VERSION 5.8 ;
BUSBITCHARS "[]" ;
DIVIDERCHAR "/" ;
UNITS
    DATABASE MICRONS 1000 ;
END UNITS

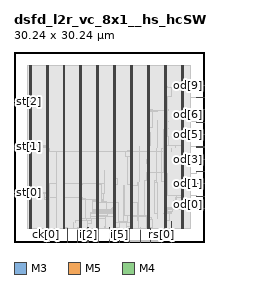
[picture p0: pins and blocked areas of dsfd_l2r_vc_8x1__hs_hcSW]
MACRO dsfd_l2r_vc_8x1__hs_hcSW
  FOREIGN dsfd_l2r_vc_8x1__hs_hcSW 0 0 ;
  CLASS BLOCK ;
  SIZE 30.24 BY 30.24 ;
  PIN ck[0]
    DIRECTION INPUT ;
    USE SIGNAL ;
    PORT
      LAYER M3 ;
        RECT  5.148 0 5.166 0.144 ;
    END
    PORT
      LAYER M3 ;
        RECT  5.148 0.108 5.166 0.173 ;
    END
  END ck[0]
  PIN cks[0]
    DIRECTION INPUT ;
    USE SIGNAL ;
    PORT
      LAYER M5 ;
        RECT  6.816 0 6.84 0.192 ;
    END
    PORT
      LAYER M5 ;
        RECT  6.816 0.144 6.84 2.137 ;
    END
  END cks[0]
  PIN fo[0]
    DIRECTION OUTPUT ;
    USE SIGNAL ;
    PORT
      LAYER M4 ;
        RECT  30.048 5.328 30.24 5.352 ;
    END
    PORT
      LAYER M4 ;
        RECT  27.004 5.328 30.06 5.352 ;
    END
  END fo[0]
  PIN i[0]
    DIRECTION INPUT ;
    USE SIGNAL ;
    PORT
      LAYER M3 ;
        RECT  8.46 0 8.478 0.144 ;
    END
    PORT
      LAYER M3 ;
        RECT  8.46 0.108 8.478 2.143 ;
    END
  END i[0]
  PIN i[1]
    DIRECTION INPUT ;
    USE SIGNAL ;
    PORT
      LAYER M5 ;
        RECT  10.128 0 10.152 0.192 ;
    END
    PORT
      LAYER M5 ;
        RECT  10.128 0.144 10.152 1.763 ;
    END
  END i[1]
  PIN i[2]
    DIRECTION INPUT ;
    USE SIGNAL ;
    PORT
      LAYER M3 ;
        RECT  11.772 0 11.79 0.144 ;
    END
    PORT
      LAYER M3 ;
        RECT  11.772 0.108 11.79 2.255 ;
    END
  END i[2]
  PIN i[3]
    DIRECTION INPUT ;
    USE SIGNAL ;
    PORT
      LAYER M5 ;
        RECT  13.44 0 13.464 0.192 ;
    END
    PORT
      LAYER M5 ;
        RECT  13.44 0.144 13.464 2.137 ;
    END
  END i[3]
  PIN i[4]
    DIRECTION INPUT ;
    USE SIGNAL ;
    PORT
      LAYER M3 ;
        RECT  15.12 0 15.138 0.144 ;
    END
    PORT
      LAYER M3 ;
        RECT  15.12 0.108 15.138 2.255 ;
    END
  END i[4]
  PIN i[5]
    DIRECTION INPUT ;
    USE SIGNAL ;
    PORT
      LAYER M5 ;
        RECT  16.752 0 16.776 0.192 ;
    END
    PORT
      LAYER M5 ;
        RECT  16.752 0.144 16.776 1.763 ;
    END
  END i[5]
  PIN i[6]
    DIRECTION INPUT ;
    USE SIGNAL ;
    PORT
      LAYER M3 ;
        RECT  18.432 0 18.45 0.144 ;
    END
    PORT
      LAYER M3 ;
        RECT  18.432 0.108 18.45 0.139 ;
    END
    PORT
      LAYER M3 ;
        RECT  17.856 0.139 18.45 2.143 ;
    END
  END i[6]
  PIN i[7]
    DIRECTION INPUT ;
    USE SIGNAL ;
    PORT
      LAYER M5 ;
        RECT  20.112 0 20.136 0.192 ;
    END
    PORT
      LAYER M5 ;
        RECT  20.112 0.144 20.136 1.763 ;
    END
  END i[7]
  PIN i[8]
    DIRECTION INPUT ;
    USE SIGNAL ;
    PORT
      LAYER M3 ;
        RECT  21.744 0 21.762 0.144 ;
    END
    PORT
      LAYER M3 ;
        RECT  21.744 0.108 21.762 2.143 ;
    END
  END i[8]
  PIN od[0]
    DIRECTION OUTPUT ;
    USE SIGNAL ;
    PORT
      LAYER M4 ;
        RECT  30.048 7.296 30.24 7.32 ;
    END
    PORT
      LAYER M4 ;
        RECT  29.041 7.296 30.06 7.32 ;
    END
  END od[0]
  PIN od[1]
    DIRECTION OUTPUT ;
    USE SIGNAL ;
    PORT
      LAYER M4 ;
        RECT  30.048 9.264 30.24 9.288 ;
    END
    PORT
      LAYER M4 ;
        RECT  29.077 9.264 30.06 9.288 ;
    END
  END od[1]
  PIN od[2]
    DIRECTION OUTPUT ;
    USE SIGNAL ;
    PORT
      LAYER M4 ;
        RECT  30.048 11.184 30.24 11.208 ;
    END
    PORT
      LAYER M4 ;
        RECT  29.077 11.184 30.06 11.208 ;
    END
  END od[2]
  PIN od[3]
    DIRECTION OUTPUT ;
    USE SIGNAL ;
    PORT
      LAYER M4 ;
        RECT  30.048 13.152 30.24 13.176 ;
    END
    PORT
      LAYER M4 ;
        RECT  29.653 13.152 30.06 13.176 ;
    END
  END od[3]
  PIN od[4]
    DIRECTION OUTPUT ;
    USE SIGNAL ;
    PORT
      LAYER M4 ;
        RECT  30.048 15.12 30.24 15.144 ;
    END
    PORT
      LAYER M4 ;
        RECT  29.041 15.12 30.06 15.144 ;
    END
  END od[4]
  PIN od[5]
    DIRECTION OUTPUT ;
    USE SIGNAL ;
    PORT
      LAYER M4 ;
        RECT  30.048 17.088 30.24 17.112 ;
    END
    PORT
      LAYER M4 ;
        RECT  29.077 17.088 30.06 17.112 ;
    END
  END od[5]
  PIN od[6]
    DIRECTION OUTPUT ;
    USE SIGNAL ;
    PORT
      LAYER M4 ;
        RECT  30.048 19.056 30.24 19.08 ;
    END
    PORT
      LAYER M4 ;
        RECT  29.077 19.056 30.06 19.08 ;
    END
  END od[6]
  PIN od[7]
    DIRECTION OUTPUT ;
    USE SIGNAL ;
    PORT
      LAYER M4 ;
        RECT  30.048 21.024 30.24 21.048 ;
    END
    PORT
      LAYER M4 ;
        RECT  29.077 21.024 30.06 21.048 ;
    END
  END od[7]
  PIN od[8]
    DIRECTION OUTPUT ;
    USE SIGNAL ;
    PORT
      LAYER M4 ;
        RECT  30.048 22.992 30.24 23.016 ;
    END
    PORT
      LAYER M4 ;
        RECT  29.041 22.992 30.06 23.016 ;
    END
  END od[8]
  PIN od[9]
    DIRECTION OUTPUT ;
    USE SIGNAL ;
    PORT
      LAYER M4 ;
        RECT  30.048 24.96 30.24 24.984 ;
    END
    PORT
      LAYER M4 ;
        RECT  29.653 24.96 30.06 24.984 ;
    END
  END od[9]
  PIN rs[0]
    DIRECTION INPUT ;
    USE SIGNAL ;
    PORT
      LAYER M5 ;
        RECT  23.424 0 23.448 0.192 ;
    END
    PORT
      LAYER M5 ;
        RECT  23.424 0.144 23.544 0.275 ;
    END
  END rs[0]
  PIN rss[0]
    DIRECTION INPUT ;
    USE SIGNAL ;
    PORT
      LAYER M3 ;
        RECT  25.092 0 25.11 0.144 ;
    END
    PORT
      LAYER M3 ;
        RECT  25.092 0.108 25.11 3.335 ;
    END
  END rss[0]
  PIN st[0]
    DIRECTION OUTPUT ;
    USE SIGNAL ;
    PORT
      LAYER M4 ;
        RECT  0 7.92 0.192 7.944 ;
    END
    PORT
      LAYER M4 ;
        RECT  0.156 7.92 2.408 7.944 ;
    END
  END st[0]
  PIN st[1]
    DIRECTION OUTPUT ;
    USE SIGNAL ;
    PORT
      LAYER M4 ;
        RECT  0 15.12 0.192 15.144 ;
    END
    PORT
      LAYER M4 ;
        RECT  0.156 15.12 2.408 15.144 ;
    END
  END st[1]
  PIN st[2]
    DIRECTION OUTPUT ;
    USE SIGNAL ;
    PORT
      LAYER M4 ;
        RECT  0 22.32 0.192 22.344 ;
    END
    PORT
      LAYER M4 ;
        RECT  0.156 22.32 0.245 22.344 ;
    END
  END st[2]
  PIN VDD
    DIRECTION INOUT ;
    USE POWER ;
    PORT
      LAYER M5 ;
        RECT  26.892 2.151 27.012 28.089 ;
        RECT  24.192 2.151 24.312 28.089 ;
        RECT  21.492 2.151 21.612 28.089 ;
        RECT  18.792 2.151 18.912 28.089 ;
        RECT  16.092 2.151 16.212 28.089 ;
        RECT  13.392 2.151 13.512 28.089 ;
        RECT  10.692 2.151 10.812 28.089 ;
        RECT  7.992 2.151 8.112 28.089 ;
        RECT  5.292 2.151 5.412 28.089 ;
        RECT  2.592 2.151 2.712 28.089 ;
    END
  END VDD
  PIN VSS
    DIRECTION INOUT ;
    USE GROUND ;
    PORT
      LAYER M5 ;
        RECT  26.7 2.137 26.82 28.103 ;
        RECT  24 2.137 24.12 28.103 ;
        RECT  21.3 2.137 21.42 28.103 ;
        RECT  18.6 2.137 18.72 28.103 ;
        RECT  15.9 2.137 16.02 28.103 ;
        RECT  13.2 2.137 13.32 28.103 ;
        RECT  10.5 2.137 10.62 28.103 ;
        RECT  7.8 2.137 7.92 28.103 ;
        RECT  5.1 2.137 5.22 28.103 ;
        RECT  2.4 2.137 2.52 28.103 ;
    END
  END VSS
  # OT_OBS_CLOSED layer=M5 d_um=1.536 added=5
  OBS
    LAYER RVTN ;
     RECT  2.16 2.16 28.08 2.295 ;
     RECT  2.16 2.565 28.08 2.835 ;
     RECT  2.16 3.105 28.08 3.375 ;
     RECT  2.16 3.645 28.08 3.915 ;
     RECT  2.16 4.185 28.08 4.455 ;
     RECT  2.16 4.725 28.08 4.995 ;
     RECT  2.16 5.265 28.08 5.535 ;
     RECT  2.16 5.805 28.08 6.075 ;
     RECT  2.16 6.345 28.08 6.615 ;
     RECT  2.16 6.885 28.08 7.155 ;
     RECT  2.16 7.425 28.08 7.695 ;
     RECT  2.16 7.965 28.08 8.235 ;
     RECT  2.16 8.505 28.08 8.775 ;
     RECT  2.16 9.045 28.08 9.315 ;
     RECT  2.16 9.585 28.08 9.855 ;
     RECT  2.16 10.125 28.08 10.395 ;
     RECT  2.16 10.665 28.08 10.935 ;
     RECT  2.16 11.205 28.08 11.475 ;
     RECT  2.16 11.745 28.08 12.015 ;
     RECT  2.16 12.285 28.08 12.555 ;
     RECT  2.16 12.825 28.08 13.095 ;
     RECT  2.16 13.365 28.08 13.635 ;
     RECT  2.16 13.905 28.08 14.175 ;
     RECT  2.16 14.445 28.08 14.715 ;
     RECT  2.16 14.985 28.08 15.255 ;
     RECT  2.16 15.525 28.08 15.795 ;
     RECT  2.16 16.065 28.08 16.335 ;
     RECT  2.16 16.605 28.08 16.875 ;
     RECT  2.16 17.145 28.08 17.415 ;
     RECT  2.16 17.685 28.08 17.955 ;
     RECT  2.16 18.225 28.08 18.495 ;
     RECT  2.16 18.765 28.08 19.035 ;
     RECT  2.16 19.305 28.08 19.575 ;
     RECT  2.16 19.845 28.08 20.115 ;
     RECT  2.16 20.385 28.08 20.655 ;
     RECT  2.16 20.925 28.08 21.195 ;
     RECT  2.16 21.465 28.08 21.735 ;
     RECT  2.16 22.005 28.08 22.275 ;
     RECT  2.16 22.545 28.08 22.815 ;
     RECT  2.16 23.085 28.08 23.355 ;
     RECT  2.16 23.625 28.08 23.895 ;
     RECT  2.16 24.165 28.08 24.435 ;
     RECT  2.16 24.705 28.08 24.975 ;
     RECT  2.16 25.245 28.08 25.515 ;
     RECT  2.16 25.785 28.08 26.055 ;
     RECT  2.16 26.325 28.08 26.595 ;
     RECT  2.16 26.865 28.08 27.135 ;
     RECT  2.16 27.405 28.08 27.675 ;
     RECT  2.16 27.945 28.08 28.08 ;
    LAYER RVTP ;
     RECT  2.16 2.295 28.08 2.565 ;
     RECT  2.16 2.835 28.08 3.105 ;
     RECT  2.16 3.375 28.08 3.645 ;
     RECT  2.16 3.915 28.08 4.185 ;
     RECT  2.16 4.455 28.08 4.725 ;
     RECT  2.16 4.995 28.08 5.265 ;
     RECT  2.16 5.535 28.08 5.805 ;
     RECT  2.16 6.075 28.08 6.345 ;
     RECT  2.16 6.615 28.08 6.885 ;
     RECT  2.16 7.155 28.08 7.425 ;
     RECT  2.16 7.695 28.08 7.965 ;
     RECT  2.16 8.235 28.08 8.505 ;
     RECT  2.16 8.775 28.08 9.045 ;
     RECT  2.16 9.315 28.08 9.585 ;
     RECT  2.16 9.855 28.08 10.125 ;
     RECT  2.16 10.395 28.08 10.665 ;
     RECT  2.16 10.935 28.08 11.205 ;
     RECT  2.16 11.475 28.08 11.745 ;
     RECT  2.16 12.015 28.08 12.285 ;
     RECT  2.16 12.555 28.08 12.825 ;
     RECT  2.16 13.095 28.08 13.365 ;
     RECT  2.16 13.635 28.08 13.905 ;
     RECT  2.16 14.175 28.08 14.445 ;
     RECT  2.16 14.715 28.08 14.985 ;
     RECT  2.16 15.255 28.08 15.525 ;
     RECT  2.16 15.795 28.08 16.065 ;
     RECT  2.16 16.335 28.08 16.605 ;
     RECT  2.16 16.875 28.08 17.145 ;
     RECT  2.16 17.415 28.08 17.685 ;
     RECT  2.16 17.955 28.08 18.225 ;
     RECT  2.16 18.495 28.08 18.765 ;
     RECT  2.16 19.035 28.08 19.305 ;
     RECT  2.16 19.575 28.08 19.845 ;
     RECT  2.16 20.115 28.08 20.385 ;
     RECT  2.16 20.655 28.08 20.925 ;
     RECT  2.16 21.195 28.08 21.465 ;
     RECT  2.16 21.735 28.08 22.005 ;
     RECT  2.16 22.275 28.08 22.545 ;
     RECT  2.16 22.815 28.08 23.085 ;
     RECT  2.16 23.355 28.08 23.625 ;
     RECT  2.16 23.895 28.08 24.165 ;
     RECT  2.16 24.435 28.08 24.705 ;
     RECT  2.16 24.975 28.08 25.245 ;
     RECT  2.16 25.515 28.08 25.785 ;
     RECT  2.16 26.055 28.08 26.325 ;
     RECT  2.16 26.595 28.08 26.865 ;
     RECT  2.16 27.135 28.08 27.405 ;
     RECT  2.16 27.675 28.08 27.945 ;
    LAYER M1 ;
     RECT  2.16 2.151 28.08 28.089 ;
    LAYER M2 ;
     RECT  0.211 22.212 2.16 22.23 ;
     RECT  2.16 2.151 28.08 28.089 ;
     RECT  28.08 7.326 29.075 7.344 ;
     RECT  28.08 15.156 29.075 15.174 ;
     RECT  28.08 22.986 29.075 23.004 ;
     RECT  28.08 9.09 29.111 9.108 ;
     RECT  28.08 10.836 29.111 10.854 ;
     RECT  28.08 16.956 29.111 16.974 ;
     RECT  28.08 19.206 29.111 19.224 ;
     RECT  28.08 21.096 29.111 21.114 ;
     RECT  28.08 13.032 29.687 13.05 ;
     RECT  28.08 24.606 29.687 24.624 ;
    LAYER M3 ;
     RECT  10.152 1.723 10.17 2.143 ;
     RECT  13.464 1.723 13.482 2.143 ;
     RECT  13.215 2.143 13.482 2.191 ;
     RECT  15.915 2.143 16.005 2.191 ;
     RECT  16.776 1.723 16.794 2.191 ;
     RECT  7.815 2.143 8.478 2.255 ;
     RECT  10.152 2.143 10.605 2.255 ;
     RECT  15.915 2.191 16.794 2.255 ;
     RECT  20.16 1.723 20.178 2.255 ;
     RECT  21.315 2.143 21.762 2.263 ;
     RECT  21.024 2.263 21.762 2.371 ;
     RECT  2.415 2.143 2.505 2.413 ;
     RECT  5.115 2.143 5.205 2.413 ;
     RECT  10.515 2.255 10.605 2.413 ;
     RECT  13.068 2.191 13.482 2.413 ;
     RECT  17.856 2.143 18.705 2.413 ;
     RECT  24.015 2.143 24.105 2.413 ;
     RECT  26.715 2.143 26.805 2.413 ;
     RECT  14.436 2.371 14.634 2.489 ;
     RECT  11.7 2.263 11.718 3.001 ;
     RECT  9.396 2.191 9.414 3.029 ;
     RECT  15.915 2.255 16.722 3.029 ;
     RECT  17.856 2.413 18.897 3.181 ;
     RECT  15.915 3.029 16.578 3.197 ;
     RECT  19.764 2.263 19.782 3.343 ;
     RECT  24.015 2.413 24.297 3.379 ;
     RECT  11.7 3.001 12.258 3.403 ;
     RECT  9.72 3.181 9.738 3.437 ;
     RECT  21.024 2.371 22.086 3.569 ;
     RECT  11.556 3.403 12.258 3.721 ;
     RECT  13.068 2.413 13.497 3.721 ;
     RECT  14.616 2.489 14.634 3.721 ;
     RECT  15.915 3.197 16.197 3.721 ;
     RECT  11.556 3.721 14.634 3.749 ;
     RECT  21.024 3.569 21.906 3.965 ;
     RECT  19.728 3.343 19.782 4.117 ;
     RECT  12.24 3.749 14.634 4.123 ;
     RECT  17.496 3.181 18.897 4.157 ;
     RECT  19.728 4.117 19.818 4.157 ;
     RECT  19.728 4.157 19.782 4.217 ;
     RECT  15.876 3.721 16.197 4.261 ;
     RECT  21.024 3.965 21.597 4.261 ;
     RECT  15.768 4.261 16.197 4.495 ;
     RECT  24.015 3.379 24.75 4.495 ;
     RECT  12.24 4.123 14.958 4.531 ;
     RECT  15.732 4.495 16.197 4.531 ;
     RECT  22.86 3.721 22.878 4.531 ;
     RECT  23.796 4.495 24.75 4.531 ;
     RECT  23.796 4.531 25.038 4.541 ;
     RECT  23.94 4.541 25.038 4.649 ;
     RECT  12.24 4.531 16.254 4.685 ;
     RECT  12.492 4.685 16.254 4.793 ;
     RECT  24.015 4.649 25.038 4.801 ;
     RECT  12.492 4.793 16.218 4.991 ;
     RECT  26.715 2.413 26.997 5.179 ;
     RECT  12.492 4.991 16.197 5.189 ;
     RECT  26.316 5.179 26.997 5.225 ;
     RECT  24.015 4.801 25.182 5.227 ;
     RECT  15.48 5.189 16.197 5.369 ;
     RECT  15.732 5.369 16.197 5.495 ;
     RECT  24.015 5.227 25.902 5.495 ;
     RECT  15.768 5.495 16.197 6.115 ;
     RECT  15.768 6.115 16.362 6.235 ;
     RECT  15.768 6.235 16.578 6.275 ;
     RECT  18.615 4.157 18.897 6.349 ;
     RECT  19.728 4.217 19.746 6.349 ;
     RECT  12.492 5.189 14.67 6.413 ;
     RECT  25.344 5.495 25.902 6.539 ;
     RECT  12.492 6.413 14.238 6.575 ;
     RECT  13.212 6.575 14.238 6.647 ;
     RECT  5.115 2.413 5.397 6.691 ;
     RECT  10.515 2.413 10.797 6.715 ;
     RECT  13.212 6.647 14.166 6.809 ;
     RECT  10.515 6.715 11.322 6.845 ;
     RECT  4.788 6.691 5.397 7.051 ;
     RECT  25.74 6.539 25.902 7.051 ;
     RECT  26.715 5.225 26.997 7.051 ;
     RECT  25.74 7.051 26.997 7.115 ;
     RECT  10.515 6.845 10.818 7.133 ;
     RECT  25.884 7.115 26.997 7.349 ;
     RECT  29.052 7.291 29.07 7.349 ;
     RECT  25.884 7.349 25.902 7.421 ;
     RECT  2.415 2.413 2.697 7.735 ;
     RECT  4.788 7.051 5.67 7.771 ;
     RECT  13.215 6.809 14.166 7.771 ;
     RECT  2.415 7.735 3.222 7.889 ;
     RECT  4.644 7.771 5.67 7.949 ;
     RECT  2.415 7.889 2.97 7.961 ;
     RECT  18.615 6.349 19.746 8.969 ;
     RECT  15.768 6.275 16.197 9.005 ;
     RECT  17.496 4.157 17.514 9.005 ;
     RECT  24.015 5.495 24.297 9.067 ;
     RECT  15.876 9.005 16.197 9.085 ;
     RECT  18.615 8.969 18.897 9.085 ;
     RECT  10.515 7.133 10.797 9.115 ;
     RECT  13.215 7.771 14.454 9.239 ;
     RECT  6.84 9.115 6.858 9.293 ;
     RECT  10.515 9.115 10.854 9.293 ;
     RECT  13.215 9.239 13.698 9.293 ;
     RECT  29.088 9.085 29.106 9.293 ;
     RECT  19.728 8.969 19.746 9.545 ;
     RECT  22.428 4.531 22.878 9.545 ;
     RECT  24.012 9.067 24.297 9.661 ;
     RECT  20.736 4.261 21.597 9.815 ;
     RECT  22.428 9.545 22.734 9.815 ;
     RECT  15.876 9.085 16.542 10.085 ;
     RECT  5.115 7.949 5.67 10.769 ;
     RECT  14.436 9.239 14.454 10.831 ;
     RECT  14.328 10.831 14.454 10.859 ;
     RECT  21.096 9.815 21.597 10.859 ;
     RECT  29.088 10.831 29.106 11.213 ;
     RECT  14.328 10.859 14.346 11.399 ;
     RECT  21.204 10.859 21.597 12.523 ;
     RECT  21.096 12.523 21.597 13.055 ;
     RECT  29.664 13.027 29.682 13.181 ;
     RECT  15.876 10.085 16.197 13.559 ;
     RECT  18.108 9.085 18.897 13.639 ;
     RECT  17.676 13.639 18.897 14.405 ;
     RECT  18.108 14.405 18.897 14.639 ;
     RECT  2.415 7.961 2.697 14.881 ;
     RECT  5.115 10.769 5.598 14.909 ;
     RECT  22.716 9.815 22.734 14.909 ;
     RECT  23.472 9.661 24.297 14.909 ;
     RECT  25.092 14.341 25.11 14.909 ;
     RECT  5.115 14.909 5.562 15.061 ;
     RECT  26.715 7.349 26.997 15.061 ;
     RECT  2.304 14.881 2.697 15.149 ;
     RECT  19.944 9.661 19.962 15.179 ;
     RECT  21.204 13.055 21.597 15.179 ;
     RECT  26.676 15.061 26.997 15.179 ;
     RECT  29.052 15.115 29.07 15.179 ;
     RECT  4.68 15.061 5.562 15.215 ;
     RECT  21.276 15.179 21.597 15.331 ;
     RECT  4.68 15.215 5.397 15.359 ;
     RECT  25.74 15.025 25.758 15.389 ;
     RECT  21.276 15.331 21.69 16.025 ;
     RECT  23.976 14.909 24.297 16.141 ;
     RECT  23.796 16.141 24.297 16.747 ;
     RECT  23.796 16.747 24.642 16.799 ;
     RECT  23.796 16.799 24.297 16.979 ;
     RECT  29.088 16.951 29.106 17.117 ;
     RECT  21.315 16.025 21.69 17.375 ;
     RECT  23.94 16.979 24.297 18.091 ;
     RECT  21.315 17.375 21.597 18.301 ;
     RECT  23.94 18.091 24.498 19.111 ;
     RECT  23.94 19.111 24.57 19.139 ;
     RECT  23.976 19.139 24.57 19.229 ;
     RECT  29.088 19.051 29.106 19.229 ;
     RECT  22.86 15.061 22.878 19.265 ;
     RECT  23.976 19.229 24.498 20.075 ;
     RECT  21.315 18.301 22.086 20.821 ;
     RECT  21.315 20.821 22.374 20.827 ;
     RECT  21.315 20.827 22.842 20.861 ;
     RECT  22.824 20.861 22.842 20.957 ;
     RECT  24.015 20.075 24.498 21.001 ;
     RECT  21.315 20.861 22.086 21.029 ;
     RECT  29.088 21.019 29.106 21.119 ;
     RECT  24.015 21.001 24.534 21.155 ;
     RECT  0.216 22.207 0.234 22.349 ;
     RECT  29.052 22.981 29.07 23.021 ;
     RECT  24.015 21.155 24.498 23.125 ;
     RECT  24.015 23.125 25.11 23.165 ;
     RECT  24.015 23.165 24.462 24.523 ;
     RECT  24.015 24.523 24.534 24.629 ;
     RECT  24.015 24.629 24.462 24.809 ;
     RECT  29.664 24.601 29.682 24.989 ;
     RECT  2.415 15.149 2.697 27.827 ;
     RECT  5.115 15.359 5.397 27.827 ;
     RECT  7.815 2.255 8.097 27.827 ;
     RECT  10.515 9.293 10.797 27.827 ;
     RECT  13.215 9.293 13.497 27.827 ;
     RECT  15.915 13.559 16.197 27.827 ;
     RECT  18.615 14.639 18.897 27.827 ;
     RECT  21.315 21.029 21.597 27.827 ;
     RECT  24.015 24.809 24.297 27.827 ;
     RECT  26.715 15.179 26.997 27.827 ;
     RECT  2.415 27.827 2.505 28.097 ;
     RECT  5.115 27.827 5.205 28.097 ;
     RECT  7.815 27.827 7.905 28.097 ;
     RECT  10.515 27.827 10.605 28.097 ;
     RECT  13.215 27.827 13.305 28.097 ;
     RECT  15.915 27.827 16.005 28.097 ;
     RECT  18.615 27.827 18.705 28.097 ;
     RECT  21.315 27.827 21.405 28.097 ;
     RECT  24.015 27.827 24.105 28.097 ;
     RECT  26.715 27.827 26.805 28.097 ;
    LAYER M4 ;
     RECT  2.408 2.148 2.512 28.092 ;
     RECT  2.512 2.418 2.704 27.822 ;
     RECT  2.704 7.92 2.981 7.944 ;
     RECT  4.633 7.92 5.108 7.944 ;
     RECT  5.108 2.148 5.212 28.092 ;
     RECT  5.212 2.418 5.404 27.822 ;
     RECT  5.404 14.928 5.555 14.952 ;
     RECT  5.137 0.144 5.603 0.168 ;
     RECT  5.404 7.104 5.699 7.944 ;
     RECT  5.404 9.12 5.699 9.24 ;
     RECT  5.699 9.12 6.829 9.144 ;
     RECT  5.699 7.104 7.808 7.128 ;
     RECT  6.829 9.12 7.808 9.288 ;
     RECT  6.805 14.448 7.808 14.472 ;
     RECT  7.808 2.148 7.912 28.092 ;
     RECT  7.912 2.418 8.104 27.822 ;
     RECT  10.097 1.728 10.181 1.752 ;
     RECT  9.709 3.408 10.508 3.432 ;
     RECT  8.104 7.104 10.508 7.128 ;
     RECT  8.104 9.264 10.508 9.288 ;
     RECT  8.104 14.448 10.508 14.472 ;
     RECT  10.508 2.148 10.612 28.092 ;
     RECT  10.612 2.418 10.804 27.822 ;
     RECT  10.804 6.72 10.829 7.128 ;
     RECT  10.804 9.12 10.865 9.288 ;
     RECT  10.829 6.72 11.363 6.84 ;
     RECT  10.804 3.408 11.585 3.72 ;
     RECT  11.585 3.696 13.208 3.72 ;
     RECT  11.363 6.816 13.208 6.84 ;
     RECT  10.865 9.264 13.208 9.288 ;
     RECT  10.804 14.448 13.208 14.472 ;
     RECT  13.208 2.148 13.312 28.092 ;
     RECT  13.312 2.148 13.409 27.822 ;
     RECT  13.409 1.728 13.493 27.822 ;
     RECT  13.493 2.418 13.504 27.822 ;
     RECT  13.504 9.12 13.709 9.288 ;
     RECT  13.504 6.24 13.955 6.84 ;
     RECT  13.709 9.12 13.961 9.144 ;
     RECT  13.504 4.128 14.821 4.152 ;
     RECT  14.821 4.128 15.908 4.536 ;
     RECT  13.955 6.24 15.908 6.264 ;
     RECT  13.504 14.448 15.908 14.472 ;
     RECT  15.908 2.148 16.012 28.092 ;
     RECT  16.012 2.148 16.204 27.822 ;
     RECT  16.204 4.512 16.595 4.536 ;
     RECT  16.204 6.24 16.595 6.264 ;
     RECT  16.721 1.728 16.805 1.752 ;
     RECT  16.204 3.168 18.097 3.192 ;
     RECT  18.097 3.168 18.608 4.152 ;
     RECT  16.204 14.448 18.608 14.472 ;
     RECT  18.608 2.148 18.712 28.092 ;
     RECT  18.712 2.418 18.904 27.822 ;
     RECT  20.101 1.728 20.189 1.752 ;
     RECT  18.904 4.128 21.308 4.152 ;
     RECT  21.157 10.992 21.308 11.016 ;
     RECT  21.085 12.528 21.308 12.552 ;
     RECT  18.904 14.448 21.308 14.472 ;
     RECT  21.308 2.148 21.412 28.092 ;
     RECT  21.412 2.418 21.604 27.822 ;
     RECT  21.604 3.936 21.917 3.96 ;
     RECT  21.604 20.832 22.813 20.856 ;
     RECT  22.813 20.832 22.853 20.952 ;
     RECT  17.845 0.144 23.413 0.168 ;
     RECT  23.413 0.144 23.555 0.264 ;
     RECT  21.604 10.992 23.813 11.016 ;
     RECT  21.604 14.448 23.845 14.472 ;
     RECT  23.785 4.512 24.008 4.536 ;
     RECT  24.001 9.072 24.008 9.096 ;
     RECT  23.813 10.992 24.008 11.352 ;
     RECT  23.845 14.448 24.008 14.808 ;
     RECT  23.845 17.904 24.008 17.928 ;
     RECT  22.853 20.928 24.008 20.952 ;
     RECT  24.008 2.148 24.112 28.092 ;
     RECT  24.112 2.418 24.304 27.822 ;
     RECT  24.304 4.512 24.419 5.256 ;
     RECT  24.304 9.072 24.419 9.096 ;
     RECT  24.304 10.896 24.419 10.92 ;
     RECT  24.304 19.344 24.419 19.368 ;
     RECT  24.304 20.928 24.419 20.952 ;
     RECT  24.304 18.096 24.515 18.12 ;
     RECT  24.304 16.752 24.659 16.776 ;
     RECT  24.304 24.528 25.091 24.552 ;
     RECT  24.304 23.136 25.132 23.16 ;
     RECT  24.419 5.232 26.305 5.256 ;
     RECT  26.305 5.184 26.708 5.256 ;
     RECT  24.304 7.392 26.708 7.416 ;
     RECT  24.304 15.36 26.708 15.384 ;
     RECT  26.708 2.148 26.812 28.092 ;
     RECT  26.812 2.418 27.004 27.822 ;
    LAYER M5 ;
     RECT  23.52 0.133 23.544 0.144 ;
     RECT  5.568 0.133 5.592 2.137 ;
     RECT  2.4 2.137 2.52 2.151 ;
     RECT  6.816 2.137 7.92 2.151 ;
     RECT  10.5 2.137 10.62 2.151 ;
     RECT  13.2 2.137 13.464 2.151 ;
     RECT  18.6 2.137 18.72 2.151 ;
     RECT  21.3 2.137 21.42 2.151 ;
     RECT  24 2.137 24.12 2.151 ;
     RECT  26.7 2.137 26.82 2.151 ;
     RECT  15.9 2.137 16.212 3.157 ;
     RECT  10.5 2.151 10.812 3.685 ;
     RECT  24 2.151 24.312 4.501 ;
     RECT  24 4.501 24.408 5.267 ;
     RECT  13.2 2.151 13.512 6.229 ;
     RECT  15.9 3.157 16.584 6.275 ;
     RECT  10.5 3.685 11.352 6.755 ;
     RECT  5.1 2.137 5.592 7.093 ;
     RECT  24 5.267 24.312 7.381 ;
     RECT  13.2 6.229 13.944 9.155 ;
     RECT  5.1 7.093 5.688 9.251 ;
     RECT  24 7.381 24.408 10.931 ;
     RECT  21.3 2.151 21.612 10.981 ;
     RECT  24 10.931 24.312 11.317 ;
     RECT  21.168 10.981 21.612 12.563 ;
     RECT  6.816 2.151 8.112 14.483 ;
     RECT  5.1 9.251 5.544 14.963 ;
     RECT  23.856 11.317 24.312 15.349 ;
     RECT  23.856 15.349 24.648 16.787 ;
     RECT  23.856 16.787 24.504 17.939 ;
     RECT  24 17.939 24.504 18.131 ;
     RECT  24 18.131 24.312 19.333 ;
     RECT  24 19.333 24.408 23.125 ;
     RECT  24 23.125 25.08 24.563 ;
     RECT  2.4 2.151 2.712 28.089 ;
     RECT  5.1 14.963 5.412 28.089 ;
     RECT  7.8 14.483 8.112 28.089 ;
     RECT  10.5 6.755 10.812 28.089 ;
     RECT  13.2 9.155 13.512 28.089 ;
     RECT  15.9 6.275 16.212 28.089 ;
     RECT  18.6 2.151 18.912 28.089 ;
     RECT  21.3 12.563 21.612 28.089 ;
     RECT  24 24.563 24.312 28.089 ;
     RECT  26.7 2.151 27.012 28.089 ;
     RECT  2.4 28.089 2.52 28.103 ;
     RECT  5.1 28.089 5.22 28.103 ;
     RECT  7.8 28.089 7.92 28.103 ;
     RECT  10.5 28.089 10.62 28.103 ;
     RECT  13.2 28.089 13.32 28.103 ;
     RECT  15.9 28.089 16.02 28.103 ;
     RECT  18.6 28.089 18.72 28.103 ;
     RECT  21.3 28.089 21.42 28.103 ;
     RECT  24 28.089 24.12 28.103 ;
     RECT  26.7 28.089 26.82 28.103 ;
     RECT  5.592 2.137 6.768 2.185 ;
     RECT  5.592 2.185 6.816 7.093 ;
     RECT  5.688 7.093 6.816 9.251 ;
     RECT  5.544 9.251 6.816 14.483 ;
     RECT  24.312 18.131 24.408 19.333 ;
  END
END dsfd_l2r_vc_8x1__hs_hcSW
END LIBRARY
